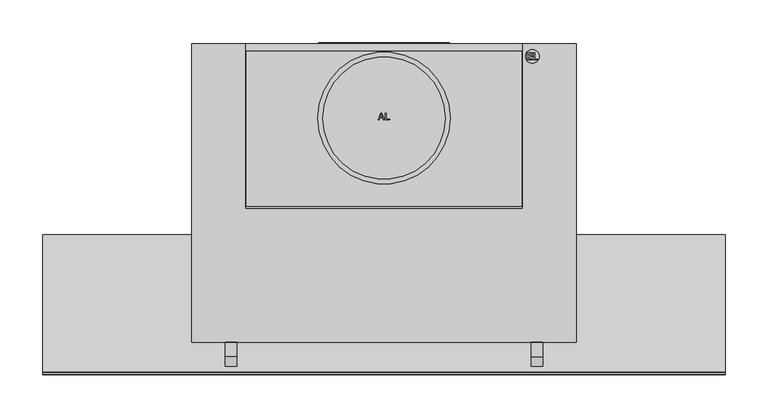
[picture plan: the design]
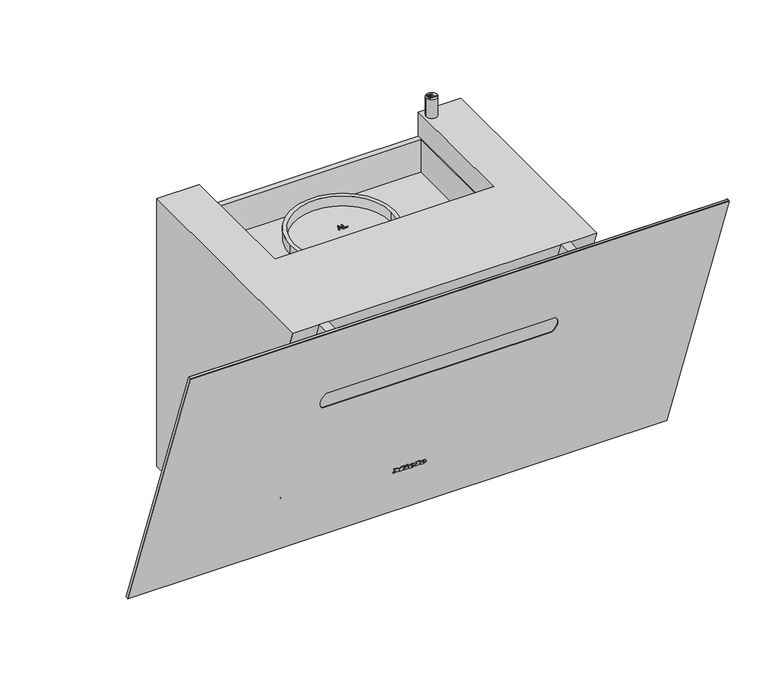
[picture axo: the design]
"""IFC4 building model written with IfcOpenShell, lengths in millimetres: proxy geometry."""

from ifc_helpers import new_model, si_unit, point, frame, frame_2d, origin, origin_with_axes, place, context, project, spatial, polyline, circle_curve, ellipse_curve, trimmed, segment, composite_curve, outline, extrude, faceted_brep, source, transform, mapped, element, save
from ifc_brep_helpers import plane_surface, cylinder_surface, revolved_surface, extruded_surface, advanced_brep


def specialty_equipment_e31fde03(model_context):
    return source(origin(), model_context, "Body", "SolidModel", [
        extrude(outline(polyline([(0.0, 0.0), (0.968, 0.0), (0.968, 5.352), (0.0, 5.352), (0.0, 6.696), (3.52, 6.696), (3.52, 5.352), (2.56, 5.352), (2.56, 1.9488753), (6.136, 6.696), (9.728, 1.8807777), (9.728, 5.352), (8.744, 5.352), (8.744, 6.696), (15.128, 6.696), (15.128, 5.352), (14.112, 5.352), (14.112, 0.0), (15.128, 0.0), (15.128, -1.304), (10.256, -1.304), (7.92, 1.696), (5.576, -1.304), (0.0, -1.304), (0.0, 0.0)])), frame((-24.271984, -261.1380975, 82.2921818), z_axis=(0.0, 0.9396926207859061, 0.34202014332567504), x_axis=(1.0, 0.0, 0.0)), (0.0, 0.0, 1.0), 1.0),
        extrude(outline(polyline([(0.0, 0.0), (0.96, 0.0), (0.96, 5.352), (0.0, 5.352), (0.0, 6.696), (6.488, 6.696), (6.488, 5.352), (5.504, 5.352), (5.504, -1.304), (0.0, -1.304), (0.0, 0.0)])), frame((8.192016, -261.1380975, 82.2921818), z_axis=(0.0, 0.9396926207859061, 0.34202014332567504), x_axis=(1.0, 0.0, 0.0)), (0.0, 0.0, 1.0), 1.0),
        extrude(outline(polyline([(0.0, 0.0), (1.4315306, 0.0), (1.4390414, -2.9920869), (0.0109086, -2.9993294), (0.0, 0.0)])), frame((-6.351984, -261.4226582, 83.074006), z_axis=(0.0, 0.9396926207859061, 0.342020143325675), x_axis=(0.42472021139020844, 0.30963927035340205, -0.8507269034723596)), (0.0, 0.0, 1.0), 1.0),
        extrude(outline(polyline([(0.4933907, 2.4141097), (1.7898156, 3.022309), (2.1941493, 2.1604399), (5.1636141, 3.5535222), (4.7592805, 4.4153913), (5.9760369, 4.9862153), (8.6568708, -0.728194), (7.4401145, -1.299018), (7.0459741, -0.4588767), (2.7800843, -2.4601583), (0.4933907, 2.4141097)])), frame((-6.351984, -261.4226582, 83.074006), z_axis=(0.0, 0.9396926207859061, 0.342020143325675), x_axis=(0.42472021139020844, 0.30963927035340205, -0.8507269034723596)), (0.0, 0.0, 1.0), 1.0),
        advanced_brep(
        [(2.392016, -259.4964008, 77.7816572), (2.392016, -259.7727531, 78.5409288), (7.744016, -259.7727531, 78.5409288), (-1.567984, -259.7727531, 78.5409288), (0.632016, -258.8479306, 76.0), (7.608016, -259.4964008, 77.7816572), (5.192016, -259.4964008, 77.7816572), (3.288016, -259.1899507, 76.9396926), (2.392016, -260.1229817, 79.5031741), (2.392016, -260.4212233, 80.3225861), (3.760016, -260.4212233, 80.3225861), (3.760016, -260.1229817, 79.5031741), (2.392016, -258.5567082, 78.1236774), (3.288016, -258.2502581, 77.2817128), (5.192016, -258.5567082, 78.1236774), (7.608016, -258.5567082, 78.1236774), (0.632016, -257.908238, 76.3420201), (-1.567984, -258.8330604, 78.882949), (7.744016, -258.8330604, 78.882949), (2.392016, -258.8330604, 78.882949), (2.392016, -259.1832891, 79.8451942), (3.760016, -259.1832891, 79.8451942), (3.760016, -259.4815306, 80.6646062), (2.392016, -259.4815306, 80.6646062)],
        [
            (0, 1),
            (1, 2),
            (2, 3, ellipse_curve(frame((3.088016, -259.7727531, 78.5409288), z_axis=(0.0, -0.9396926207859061, -0.34202014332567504), x_axis=(-1.0, 0.0, 0.0)), 4.656, 3.848)),
            (3, 4, circle_curve(frame((1.5280596, -259.8657825, 78.7965252), z_axis=(0.0, -0.9396926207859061, -0.34202014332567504), x_axis=(0.0, 0.34202014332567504, -0.9396926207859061)), 3.1079688)),
            (4, 5, circle_curve(frame((2.9948096, -260.5881291, 80.7811561), z_axis=(0.0, -0.9396926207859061, -0.34202014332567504), x_axis=(0.0, 0.34202014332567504, -0.9396926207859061)), 5.6098607)),
            (5, 6),
            (6, 7, circle_curve(frame((3.6790748, -259.7508638, 78.4807885), z_axis=(0.0, 0.9396926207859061, 0.34202014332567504), x_axis=(0.0, 0.34202014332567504, -0.9396926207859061)), 1.6859795)),
            (7, 0, circle_curve(frame((3.288016, -259.4964008, 77.7816572), z_axis=(0.0, 0.9396926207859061, 0.34202014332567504), x_axis=(0.0, 0.34202014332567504, -0.9396926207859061)), 0.896)),
            (8, 9),
            (9, 10, circle_curve(frame((3.076016, -260.4212233, 80.3225861), z_axis=(0.0, 0.9396926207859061, 0.34202014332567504), x_axis=(0.0, 0.34202014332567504, -0.9396926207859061)), 0.684)),
            (10, 11),
            (11, 8),
            (12, 13, circle_curve(frame((3.288016, -258.5567082, 78.1236774), z_axis=(0.0, -0.9396926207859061, -0.34202014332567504), x_axis=(0.0, 0.34202014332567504, -0.9396926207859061)), 0.896)),
            (13, 14, circle_curve(frame((3.6790748, -258.8111712, 78.8228087), z_axis=(0.0, -0.9396926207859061, -0.34202014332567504), x_axis=(0.0, 0.34202014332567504, -0.9396926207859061)), 1.6859795)),
            (14, 15),
            (15, 16, circle_curve(frame((2.9948096, -259.6484365, 81.1231762), z_axis=(0.0, 0.9396926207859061, 0.34202014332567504), x_axis=(0.0, 0.34202014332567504, -0.9396926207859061)), 5.6098607)),
            (16, 17, circle_curve(frame((1.5280596, -258.9260899, 79.1385454), z_axis=(0.0, 0.9396926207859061, 0.34202014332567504), x_axis=(0.0, 0.34202014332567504, -0.9396926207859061)), 3.1079688)),
            (17, 18, ellipse_curve(frame((3.088016, -258.8330604, 78.882949), z_axis=(0.0, 0.9396926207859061, 0.34202014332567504), x_axis=(-1.0, 0.0, 0.0)), 4.656, 3.848)),
            (18, 19),
            (19, 12),
            (20, 21),
            (21, 22),
            (22, 23, circle_curve(frame((3.076016, -259.4815306, 80.6646062), z_axis=(0.0, -0.9396926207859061, -0.34202014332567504), x_axis=(0.0, 0.34202014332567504, -0.9396926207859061)), 0.684)),
            (23, 20),
            (0, 12),
            (19, 1),
            (18, 2),
            (5, 15),
            (14, 6),
            (17, 3),
            (13, 7),
            (16, 4),
            (8, 20),
            (23, 9),
            (22, 10),
            (21, 11),
        ],
        [
            plane_surface(frame((2.392016, -259.7727531, 78.5409288), z_axis=(0.0, -0.9396926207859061, -0.34202014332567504), x_axis=(0.0, -0.34202014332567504, 0.9396926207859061))),
            plane_surface(frame((2.392016, -258.8330604, 78.882949), z_axis=(0.0, 0.9396926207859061, 0.34202014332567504), x_axis=(0.0, 0.34202014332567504, -0.9396926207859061))),
            plane_surface(frame((2.392016, -259.4964008, 77.7816572), z_axis=(1.0, 0.0, 0.0), x_axis=(0.0, 0.9396926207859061, 0.34202014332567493))),
            plane_surface(frame((2.392016, -259.7727531, 78.5409288), z_axis=(0.0, 0.34202014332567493, -0.9396926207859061), x_axis=(0.0, 0.9396926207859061, 0.34202014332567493))),
            plane_surface(frame((7.608016, -259.4964008, 77.7816572), z_axis=(0.0, -0.34202014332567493, 0.9396926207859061), x_axis=(0.0, 0.9396926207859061, 0.34202014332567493))),
            extruded_surface(trimmed(ellipse_curve(frame((3.088016, -257.8933678, 79.2249691), z_axis=(0.0, -0.9396926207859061, -0.34202014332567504), x_axis=(-1.0, 0.0, 0.0)), 4.656, 3.848), [point((7.744016, -257.8933678, 79.2249691))], [point((-1.567984, -257.8933678, 79.2249691))], True, "CARTESIAN"), (0.0, -0.9396926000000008, -0.34202009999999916), 0.9999999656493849),
            revolved_surface(polyline([(3.6790748, -258.2345321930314, 77.23850622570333), (3.6790748, -259.1742248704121, 76.89648606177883)]), (3.6790748, -258.8111712, 78.8228087), (0.0, 0.9396926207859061, 0.34202014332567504)),
            revolved_surface(polyline([(3.288016, -258.25025810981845, 77.28171282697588), (3.288016, -259.1899507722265, 76.93969266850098)]), (3.288016, -258.5567082, 78.1236774), (0.0, 0.9396926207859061, 0.34202014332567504)),
            cylinder_surface(frame((1.5280596, -258.9260899, 79.1385454), z_axis=(0.0, -0.9396926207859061, -0.34202014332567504), x_axis=(0.0, 0.34202014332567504, -0.9396926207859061)), 3.1079688),
            cylinder_surface(frame((2.9948096, -259.6484365, 81.1231762), z_axis=(0.0, -0.9396926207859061, -0.34202014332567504), x_axis=(0.0, 0.34202014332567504, -0.9396926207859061)), 5.6098607),
            plane_surface(frame((2.392016, -260.1229817, 79.5031741), z_axis=(1.0, 0.0, 0.0), x_axis=(0.0, 0.9396926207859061, 0.34202014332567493))),
            revolved_surface(polyline([(3.076016, -259.2475888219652, 80.02185644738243), (3.076016, -260.1872814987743, 79.67983628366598)]), (3.076016, -259.4815306, 80.6646062), (0.0, 0.9396926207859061, 0.34202014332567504)),
            plane_surface(frame((3.760016, -260.4212233, 80.3225861), z_axis=(-1.0, 0.0, 0.0), x_axis=(0.0, 0.9396926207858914, 0.3420201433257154))),
            plane_surface(frame((3.760016, -260.1229817, 79.5031741), z_axis=(0.0, -0.34202014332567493, 0.9396926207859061), x_axis=(0.0, 0.9396926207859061, 0.34202014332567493))),
        ],
        [
            (0, [[1, 2, 3, 4, 5, 6, 7, 8], [9, 10, 11, 12]]),
            (1, [[13, 14, 15, 16, 17, 18, 19, 20], [21, 22, 23, 24]]),
            (2, [[-1, 25, -20, 26]]),
            (3, [[-2, -26, -19, 27]]),
            (4, [[-6, 28, -15, 29]]),
            (5, [[-3, -27, -18, 30]]),
            (6, [[-7, -29, -14, 31]]),
            (7, [[-8, -31, -13, -25]]),
            (8, [[-4, -30, -17, 32]]),
            (9, [[-5, -32, -16, -28]]),
            (10, [[-9, 33, -24, 34]]),
            (11, [[-10, -34, -23, 35]]),
            (12, [[-11, -35, -22, 36]]),
            (13, [[-12, -36, -21, -33]]),
        ],
    ),
        advanced_brep(
        [(19.088016, -259.4964008, 77.7816572), (19.088016, -259.7727531, 78.5409288), (24.440016, -259.7727531, 78.5409288), (15.128016, -259.7727531, 78.5409288), (17.328016, -258.8479306, 76.0), (24.304016, -259.4964008, 77.7816572), (21.888016, -259.4964008, 77.7816572), (19.984016, -259.1899507, 76.9396926), (19.088016, -260.1229817, 79.5031741), (19.088016, -260.4212233, 80.3225861), (20.456016, -260.4212233, 80.3225861), (20.456016, -260.1229817, 79.5031741), (19.088016, -258.5567082, 78.1236774), (19.984016, -258.2502581, 77.2817128), (21.888016, -258.5567082, 78.1236774), (24.304016, -258.5567082, 78.1236774), (17.328016, -257.908238, 76.3420201), (15.128016, -258.8330604, 78.882949), (24.440016, -258.8330604, 78.882949), (19.088016, -258.8330604, 78.882949), (19.088016, -259.1832891, 79.8451942), (20.456016, -259.1832891, 79.8451942), (20.456016, -259.4815306, 80.6646062), (19.088016, -259.4815306, 80.6646062)],
        [
            (0, 1),
            (1, 2),
            (2, 3, ellipse_curve(frame((19.784016, -259.7727531, 78.5409288), z_axis=(0.0, -0.9396926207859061, -0.34202014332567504), x_axis=(-1.0, 0.0, 0.0)), 4.656, 3.848)),
            (3, 4, circle_curve(frame((18.2240596, -259.8657825, 78.7965252), z_axis=(0.0, -0.9396926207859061, -0.34202014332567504), x_axis=(0.0, 0.34202014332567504, -0.9396926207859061)), 3.1079688)),
            (4, 5, circle_curve(frame((19.6908096, -260.5881291, 80.7811561), z_axis=(0.0, -0.9396926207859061, -0.34202014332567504), x_axis=(0.0, 0.34202014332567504, -0.9396926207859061)), 5.6098607)),
            (5, 6),
            (6, 7, circle_curve(frame((20.3750748, -259.7508638, 78.4807885), z_axis=(0.0, 0.9396926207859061, 0.34202014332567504), x_axis=(0.0, 0.34202014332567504, -0.9396926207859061)), 1.6859795)),
            (7, 0, circle_curve(frame((19.984016, -259.4964008, 77.7816572), z_axis=(0.0, 0.9396926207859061, 0.34202014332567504), x_axis=(0.0, 0.34202014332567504, -0.9396926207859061)), 0.896)),
            (8, 9),
            (9, 10, circle_curve(frame((19.772016, -260.4212233, 80.3225861), z_axis=(0.0, 0.9396926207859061, 0.34202014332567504), x_axis=(0.0, 0.34202014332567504, -0.9396926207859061)), 0.684)),
            (10, 11),
            (11, 8),
            (12, 13, circle_curve(frame((19.984016, -258.5567082, 78.1236774), z_axis=(0.0, -0.9396926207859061, -0.34202014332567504), x_axis=(0.0, 0.34202014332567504, -0.9396926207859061)), 0.896)),
            (13, 14, circle_curve(frame((20.3750748, -258.8111712, 78.8228087), z_axis=(0.0, -0.9396926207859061, -0.34202014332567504), x_axis=(0.0, 0.34202014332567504, -0.9396926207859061)), 1.6859795)),
            (14, 15),
            (15, 16, circle_curve(frame((19.6908096, -259.6484365, 81.1231762), z_axis=(0.0, 0.9396926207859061, 0.34202014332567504), x_axis=(0.0, 0.34202014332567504, -0.9396926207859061)), 5.6098607)),
            (16, 17, circle_curve(frame((18.2240596, -258.9260899, 79.1385454), z_axis=(0.0, 0.9396926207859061, 0.34202014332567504), x_axis=(0.0, 0.34202014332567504, -0.9396926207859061)), 3.1079688)),
            (17, 18, ellipse_curve(frame((19.784016, -258.8330604, 78.882949), z_axis=(0.0, 0.9396926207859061, 0.34202014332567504), x_axis=(-1.0, 0.0, 0.0)), 4.656, 3.848)),
            (18, 19),
            (19, 12),
            (20, 21),
            (21, 22),
            (22, 23, circle_curve(frame((19.772016, -259.4815306, 80.6646062), z_axis=(0.0, -0.9396926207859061, -0.34202014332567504), x_axis=(0.0, 0.34202014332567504, -0.9396926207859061)), 0.684)),
            (23, 20),
            (0, 12),
            (19, 1),
            (18, 2),
            (5, 15),
            (14, 6),
            (17, 3),
            (13, 7),
            (16, 4),
            (8, 20),
            (23, 9),
            (22, 10),
            (21, 11),
        ],
        [
            plane_surface(frame((19.088016, -259.7727531, 78.5409288), z_axis=(0.0, -0.9396926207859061, -0.34202014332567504), x_axis=(0.0, -0.34202014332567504, 0.9396926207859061))),
            plane_surface(frame((19.088016, -258.8330604, 78.882949), z_axis=(0.0, 0.9396926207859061, 0.34202014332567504), x_axis=(0.0, 0.34202014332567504, -0.9396926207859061))),
            plane_surface(frame((19.088016, -259.4964008, 77.7816572), z_axis=(1.0, 0.0, 0.0), x_axis=(0.0, 0.9396926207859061, 0.34202014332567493))),
            plane_surface(frame((19.088016, -259.7727531, 78.5409288), z_axis=(0.0, 0.34202014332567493, -0.9396926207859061), x_axis=(0.0, 0.9396926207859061, 0.34202014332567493))),
            plane_surface(frame((24.304016, -259.4964008, 77.7816572), z_axis=(0.0, -0.34202014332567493, 0.9396926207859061), x_axis=(0.0, 0.9396926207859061, 0.34202014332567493))),
            extruded_surface(trimmed(ellipse_curve(frame((19.784016, -257.8933678, 79.2249691), z_axis=(0.0, -0.9396926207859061, -0.34202014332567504), x_axis=(-1.0, 0.0, 0.0)), 4.656, 3.848), [point((24.440016, -257.8933678, 79.2249691))], [point((15.128016, -257.8933678, 79.2249691))], True, "CARTESIAN"), (0.0, -0.9396926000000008, -0.34202009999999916), 0.9999999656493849),
            revolved_surface(polyline([(20.3750748, -258.2345321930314, 77.23850622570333), (20.3750748, -259.1742248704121, 76.89648606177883)]), (20.3750748, -258.8111712, 78.8228087), (0.0, 0.9396926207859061, 0.34202014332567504)),
            revolved_surface(polyline([(19.984016, -258.25025810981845, 77.28171282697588), (19.984016, -259.1899507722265, 76.93969266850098)]), (19.984016, -258.5567082, 78.1236774), (0.0, 0.9396926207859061, 0.34202014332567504)),
            cylinder_surface(frame((18.2240596, -258.9260899, 79.1385454), z_axis=(0.0, -0.9396926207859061, -0.34202014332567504), x_axis=(0.0, 0.34202014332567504, -0.9396926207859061)), 3.1079688),
            cylinder_surface(frame((19.6908096, -259.6484365, 81.1231762), z_axis=(0.0, -0.9396926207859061, -0.34202014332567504), x_axis=(0.0, 0.34202014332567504, -0.9396926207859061)), 5.6098607),
            plane_surface(frame((19.088016, -260.1229817, 79.5031741), z_axis=(1.0, 0.0, 0.0), x_axis=(0.0, 0.9396926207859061, 0.34202014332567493))),
            revolved_surface(polyline([(19.772016, -259.2475888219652, 80.02185644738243), (19.772016, -260.1872814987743, 79.67983628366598)]), (19.772016, -259.4815306, 80.6646062), (0.0, 0.9396926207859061, 0.34202014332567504)),
            plane_surface(frame((20.456016, -260.4212233, 80.3225861), z_axis=(-1.0, 0.0, 0.0), x_axis=(0.0, 0.9396926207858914, 0.3420201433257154))),
            plane_surface(frame((20.456016, -260.1229817, 79.5031741), z_axis=(0.0, -0.34202014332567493, 0.9396926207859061), x_axis=(0.0, 0.9396926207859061, 0.34202014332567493))),
        ],
        [
            (0, [[1, 2, 3, 4, 5, 6, 7, 8], [9, 10, 11, 12]]),
            (1, [[13, 14, 15, 16, 17, 18, 19, 20], [21, 22, 23, 24]]),
            (2, [[-1, 25, -20, 26]]),
            (3, [[-2, -26, -19, 27]]),
            (4, [[-6, 28, -15, 29]]),
            (5, [[-3, -27, -18, 30]]),
            (6, [[-7, -29, -14, 31]]),
            (7, [[-8, -31, -13, -25]]),
            (8, [[-4, -30, -17, 32]]),
            (9, [[-5, -32, -16, -28]]),
            (10, [[-9, 33, -24, 34]]),
            (11, [[-10, -34, -23, 35]]),
            (12, [[-11, -35, -22, 36]]),
            (13, [[-12, -36, -21, -33]]),
        ],
    ),
        advanced_brep(
        [(-198.5, -231.2422284, 80.5173231), (-198.5, -240.9843308, 107.2835295), (-198.5, -235.8312261, 109.4708926), (-198.5, -225.8887113, 82.1540576), (-198.5, -250.514978, 76.8365225), (-198.5, -258.1140866, 97.7149017), (-198.5, -258.4754112, 96.7430581), (-198.5, -251.4164577, 77.3487429), (-198.5, -254.9459345, 87.0459005), (-198.5, -230.9198317, 95.7906867)],
        [
            (0, 1, circle_curve(frame((-198.5, -236.1132796, 93.9004263), z_axis=(0.0, 0.9396926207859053, 0.3420201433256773), x_axis=(0.0, -0.3420201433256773, 0.9396926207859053)), 14.2420009)),
            (1, 2),
            (2, 3, circle_curve(frame((-198.5, -230.8599687, 95.8124751), z_axis=(0.0, -0.9396926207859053, -0.3420201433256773), x_axis=(0.0, -0.3420201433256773, 0.9396926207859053)), 14.5349844)),
            (3, 0),
            (4, 5, circle_curve(frame((-198.5, -254.3145323, 87.2757121), z_axis=(0.0, 0.9396926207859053, 0.3420201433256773), x_axis=(0.0, -0.3420201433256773, 0.9396926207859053)), 11.1091535)),
            (5, 1),
            (0, 4),
            (6, 7, circle_curve(frame((-198.5, -254.9459345, 87.0459005), z_axis=(0.0, 0.9396926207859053, 0.3420201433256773), x_axis=(0.0, -0.3420201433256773, 0.9396926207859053)), 10.3194996)),
            (7, 4),
            (4, 5, circle_curve(frame((-198.5, -254.3145323, 87.2757121), z_axis=(0.0, -0.9396926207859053, -0.3420201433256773), x_axis=(0.0, -0.3420201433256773, 0.9396926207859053)), 11.1091535)),
            (5, 6),
            (8, 7),
            (6, 8),
            (2, 9),
            (9, 3),
            (2, 3, circle_curve(frame((-198.5, -230.9198317, 95.7906867), z_axis=(0.0, 0.9396926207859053, 0.3420201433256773), x_axis=(0.0, -0.3420201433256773, 0.9396926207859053)), 14.535124)),
            (1, 0, circle_curve(frame((-198.5, -236.1132796, 93.9004263), z_axis=(0.0, 0.9396926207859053, 0.3420201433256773), x_axis=(0.0, -0.3420201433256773, 0.9396926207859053)), 14.2420009)),
            (7, 6, circle_curve(frame((-198.5, -254.9459345, 87.0459005), z_axis=(0.0, 0.9396926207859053, 0.3420201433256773), x_axis=(0.0, -0.3420201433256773, 0.9396926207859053)), 10.3194996)),
        ],
        [
            revolved_surface(polyline([(-198.5, -235.8312261, 109.4708926), (-198.5, -240.9843308, 107.2835295)]), (-198.5, -255.2773841, 86.9252627), (0.0, -0.9396926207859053, -0.3420201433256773)),
            revolved_surface(polyline([(-198.5, -240.9843308, 107.2835295), (-198.5, -258.1140866, 97.7149017)]), (-198.5, -255.2773841, 86.9252627), (0.0, -0.9396926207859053, -0.3420201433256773)),
            revolved_surface(polyline([(-198.5, -258.1140866, 97.7149017), (-198.5, -258.4754112, 96.7430581)]), (-198.5, -255.2773841, 86.9252627), (0.0, -0.9396926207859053, -0.3420201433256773)),
            plane_surface(frame((-198.5, -254.9459345, 87.0459005), z_axis=(0.0, -0.9396926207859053, -0.3420201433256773), x_axis=(0.0, -0.3420201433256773, 0.9396926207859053))),
            plane_surface(frame((-198.5, -230.9198317, 95.7906867), z_axis=(0.0, 0.9396926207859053, 0.3420201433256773), x_axis=(0.0, -0.3420201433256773, 0.9396926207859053))),
        ],
        [
            (0, [[1, 2, 3, 4]]),
            (1, [[5, 6, -1, 7]]),
            (2, [[8, 9, 10, 11]]),
            (3, [[12, -8, 13]]),
            (4, [[-3, 14, 15]]),
            (4, [[16, -15, -14]]),
            (0, [[17, -4, -16, -2]]),
            (1, [[-10, -7, -17, -6]]),
            (2, [[18, -11, -5, -9]]),
            (3, [[-13, -18, -12]]),
        ],
    ),
        advanced_brep(
        [(-198.5, -262.8067778, 105.2732379), (-198.5, -249.4001153, 68.4387353), (-198.5, -252.3199878, 80.8696014), (-198.5, -257.0531232, 93.8737841), (-198.5, -250.699917, 68.232867), (-198.5, -263.9348133, 104.5954458), (-198.5, -257.3173652, 86.4141564), (-198.5, -254.6865555, 87.3716928)],
        [
            (0, 1, circle_curve(frame((-198.5, -256.1034466, 86.8559866), z_axis=(0.0, 0.9396926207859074, 0.34202014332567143), x_axis=(0.0, -0.34202014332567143, 0.9396926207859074)), 19.5992294)),
            (1, 2),
            (2, 3, circle_curve(frame((-198.5, -254.6865555, 87.3716928), z_axis=(0.0, -0.9396926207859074, -0.34202014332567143), x_axis=(0.0, -0.34202014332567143, 0.9396926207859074)), 6.9193811)),
            (3, 0),
            (1, 0, circle_curve(frame((-198.5, -256.1034466, 86.8559866), z_axis=(0.0, 0.9396926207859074, 0.34202014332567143), x_axis=(0.0, -0.34202014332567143, 0.9396926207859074)), 19.5992294)),
            (3, 2, circle_curve(frame((-198.5, -254.6865555, 87.3716928), z_axis=(0.0, -0.9396926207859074, -0.34202014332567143), x_axis=(0.0, -0.34202014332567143, 0.9396926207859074)), 6.9193811)),
            (4, 5, circle_curve(frame((-198.5, -257.3173652, 86.4141564), z_axis=(0.0, 0.9396926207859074, 0.34202014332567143), x_axis=(0.0, -0.34202014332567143, 0.9396926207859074)), 19.3481241)),
            (5, 0),
            (1, 4),
            (5, 4, circle_curve(frame((-198.5, -257.3173652, 86.4141564), z_axis=(0.0, 0.9396926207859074, 0.34202014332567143), x_axis=(0.0, -0.34202014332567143, 0.9396926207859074)), 19.3481241)),
            (6, 5),
            (4, 6),
            (3, 7),
            (7, 2),
        ],
        [
            revolved_surface(polyline([(-198.5, -257.0531232, 93.8737841), (-198.5, -262.8067778, 105.2732379)]), (-198.5, -254.6865555, 87.3716928), (0.0, -0.9396926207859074, -0.34202014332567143)),
            revolved_surface(polyline([(-198.5, -262.8067778, 105.2732379), (-198.5, -263.9348133, 104.5954458)]), (-198.5, -254.6865555, 87.3716928), (0.0, -0.9396926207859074, -0.34202014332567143)),
            plane_surface(frame((-198.5, -257.3173652, 86.4141564), z_axis=(0.0, -0.9396926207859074, -0.34202014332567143), x_axis=(0.0, -0.34202014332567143, 0.9396926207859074))),
            plane_surface(frame((-198.5, -254.6865555, 87.3716928), z_axis=(0.0, 0.9396926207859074, 0.34202014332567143), x_axis=(0.0, -0.34202014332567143, 0.9396926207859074))),
        ],
        [
            (0, [[1, 2, 3, 4]]),
            (0, [[5, -4, 6, -2]]),
            (1, [[7, 8, -5, 9]]),
            (1, [[10, -9, -1, -8]]),
            (2, [[11, -7, 12]]),
            (2, [[-12, -10, -11]]),
            (3, [[-6, 13, 14]]),
            (3, [[-3, -14, -13]]),
        ],
    ),
        advanced_brep(
        [(198.5, -225.9091808, 82.1477994), (198.5, -235.8509293, 109.4625291), (198.5, -240.9843308, 107.2835295), (198.5, -231.2422284, 80.5173231), (198.5, -258.1140866, 97.7149017), (198.5, -250.514978, 76.8365225), (198.5, -230.9018417, 95.8650227), (198.5, -258.4754112, 96.7430581), (198.5, -251.4164577, 77.3487429), (198.5, -254.9459345, 87.0459005)],
        [
            (0, 1, circle_curve(frame((198.5, -230.8800551, 95.8051643), z_axis=(0.0, -0.9396926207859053, -0.3420201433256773), x_axis=(0.0, -0.3420201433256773, 0.9396926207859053)), 14.5338641)),
            (1, 2),
            (2, 3, circle_curve(frame((198.5, -236.1132796, 93.9004263), z_axis=(0.0, 0.9396926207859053, 0.3420201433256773), x_axis=(0.0, -0.3420201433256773, 0.9396926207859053)), 14.2420009)),
            (3, 0),
            (2, 4),
            (4, 5, circle_curve(frame((198.5, -254.3145323, 87.2757121), z_axis=(0.0, 0.9396926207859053, 0.3420201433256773), x_axis=(0.0, -0.3420201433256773, 0.9396926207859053)), 11.1091535)),
            (5, 3),
            (6, 1),
            (0, 6),
            (0, 1, circle_curve(frame((198.5, -230.8800551, 95.8051643), z_axis=(0.0, 0.9396926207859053, 0.3420201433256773), x_axis=(0.0, -0.3420201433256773, 0.9396926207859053)), 14.5338641)),
            (3, 2, circle_curve(frame((198.5, -236.1132796, 93.9004263), z_axis=(0.0, 0.9396926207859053, 0.3420201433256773), x_axis=(0.0, -0.3420201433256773, 0.9396926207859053)), 14.2420009)),
            (5, 4, circle_curve(frame((198.5, -254.3145323, 87.2757121), z_axis=(0.0, 0.9396926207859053, 0.3420201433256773), x_axis=(0.0, -0.3420201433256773, 0.9396926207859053)), 11.1091535)),
            (4, 7),
            (7, 8, circle_curve(frame((198.5, -254.9459345, 87.0459005), z_axis=(0.0, 0.9396926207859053, 0.3420201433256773), x_axis=(0.0, -0.3420201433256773, 0.9396926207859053)), 10.3194996)),
            (8, 5),
            (8, 7, circle_curve(frame((198.5, -254.9459345, 87.0459005), z_axis=(0.0, 0.9396926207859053, 0.3420201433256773), x_axis=(0.0, -0.3420201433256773, 0.9396926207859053)), 10.3194996)),
            (7, 9),
            (9, 8),
        ],
        [
            revolved_surface(polyline([(198.5, -240.9843308, 107.2835295), (198.5, -235.8509293, 109.4625291)]), (198.5, -255.2773841, 86.9252627), (0.0, 0.9396926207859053, 0.3420201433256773)),
            revolved_surface(polyline([(198.5, -258.1140866, 97.7149017), (198.5, -240.9843308, 107.2835295)]), (198.5, -255.2773841, 86.9252627), (0.0, 0.9396926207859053, 0.3420201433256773)),
            plane_surface(frame((198.5, -230.8800551, 95.8051643), z_axis=(0.0, 0.9396926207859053, 0.3420201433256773), x_axis=(0.0, -0.3420201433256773, 0.9396926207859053))),
            revolved_surface(polyline([(198.5, -258.4754112, 96.7430581), (198.5, -258.1140866, 97.7149017)]), (198.5, -255.2773841, 86.9252627), (0.0, 0.9396926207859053, 0.3420201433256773)),
            plane_surface(frame((198.5, -254.9459345, 87.0459005), z_axis=(0.0, -0.9396926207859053, -0.3420201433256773), x_axis=(0.0, -0.3420201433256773, 0.9396926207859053))),
        ],
        [
            (0, [[1, 2, 3, 4]]),
            (1, [[-3, 5, 6, 7]]),
            (2, [[8, -1, 9]]),
            (2, [[-9, 10, -8]]),
            (0, [[-10, -4, 11, -2]]),
            (1, [[-11, -7, 12, -5]]),
            (3, [[-6, 13, 14, 15]]),
            (3, [[-12, -15, 16, -13]]),
            (4, [[-14, 17, 18]]),
            (4, [[-16, -18, -17]]),
        ],
    ),
        advanced_brep(
        [(198.5, -252.3199878, 80.8696014), (198.5, -257.0531232, 93.8737841), (198.5, -262.8067778, 105.2732379), (198.5, -249.4001153, 68.4387353), (198.5, -263.9348133, 104.5954458), (198.5, -250.699917, 68.232867), (198.5, -257.3173652, 86.4141564), (198.5, -254.6865555, 87.3716928)],
        [
            (0, 1, circle_curve(frame((198.5, -254.6865555, 87.3716928), z_axis=(0.0, -0.9396926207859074, -0.34202014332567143), x_axis=(0.0, -0.34202014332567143, 0.9396926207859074)), 6.9193811)),
            (1, 2),
            (2, 3, circle_curve(frame((198.5, -256.1034466, 86.8559866), z_axis=(0.0, 0.9396926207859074, 0.34202014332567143), x_axis=(0.0, -0.34202014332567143, 0.9396926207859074)), 19.5992294)),
            (3, 0),
            (1, 0, circle_curve(frame((198.5, -254.6865555, 87.3716928), z_axis=(0.0, -0.9396926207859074, -0.34202014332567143), x_axis=(0.0, -0.34202014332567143, 0.9396926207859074)), 6.9193811)),
            (3, 2, circle_curve(frame((198.5, -256.1034466, 86.8559866), z_axis=(0.0, 0.9396926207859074, 0.34202014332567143), x_axis=(0.0, -0.34202014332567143, 0.9396926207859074)), 19.5992294)),
            (2, 4),
            (4, 5, circle_curve(frame((198.5, -257.3173652, 86.4141564), z_axis=(0.0, 0.9396926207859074, 0.34202014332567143), x_axis=(0.0, -0.34202014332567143, 0.9396926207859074)), 19.3481241)),
            (5, 3),
            (5, 4, circle_curve(frame((198.5, -257.3173652, 86.4141564), z_axis=(0.0, 0.9396926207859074, 0.34202014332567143), x_axis=(0.0, -0.34202014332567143, 0.9396926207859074)), 19.3481241)),
            (4, 6),
            (6, 5),
            (7, 1),
            (0, 7),
        ],
        [
            revolved_surface(polyline([(198.5, -262.8067778, 105.2732379), (198.5, -257.0531232, 93.8737841)]), (198.5, -254.6865555, 87.3716928), (0.0, 0.9396926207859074, 0.34202014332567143)),
            revolved_surface(polyline([(198.5, -263.9348133, 104.5954458), (198.5, -262.8067778, 105.2732379)]), (198.5, -254.6865555, 87.3716928), (0.0, 0.9396926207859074, 0.34202014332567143)),
            plane_surface(frame((198.5, -257.3173652, 86.4141564), z_axis=(0.0, -0.9396926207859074, -0.34202014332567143), x_axis=(0.0, -0.34202014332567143, 0.9396926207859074))),
            plane_surface(frame((198.5, -254.6865555, 87.3716928), z_axis=(0.0, 0.9396926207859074, 0.34202014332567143), x_axis=(0.0, -0.34202014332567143, 0.9396926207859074))),
        ],
        [
            (0, [[1, 2, 3, 4]]),
            (0, [[5, -4, 6, -2]]),
            (1, [[-3, 7, 8, 9]]),
            (1, [[-6, -9, 10, -7]]),
            (2, [[-8, 11, 12]]),
            (2, [[-10, -12, -11]]),
            (3, [[13, -1, 14]]),
            (3, [[-14, -5, -13]]),
        ],
    ),
        extrude(outline(polyline([(-377.2541471, 415.9959153), (-366.2530147, 420.0), (-348.8949883, 420.0), (-315.0686278, 327.0628384), (-321.2276447, 324.8211395), (-334.9582954, 325.4920509), (-347.6637142, 334.6968691), (-377.2541471, 415.9959153)])), frame((-185.7167767, 0.0, 0.0), z_axis=(1.0, 0.0, 0.0), x_axis=(0.0, 1.0, 0.0)), (0.0, 0.0, 1.0), 13.4088513),
        extrude(outline(polyline([(-377.2541471, 415.9959153), (-366.2530147, 420.0), (-348.8949883, 420.0), (-315.0686278, 327.0628384), (-321.2276447, 324.8211395), (-334.9582954, 325.4920509), (-347.6637142, 334.6968691), (-377.2541471, 415.9959153)])), frame((172.3079253, 0.0, 0.0), z_axis=(1.0, 0.0, 0.0), x_axis=(0.0, 1.0, 0.0)), (0.0, 0.0, 1.0), 13.4088513),
        advanced_brep(
        [(399.0, -387.3899893, 432.0882368), (399.0, -387.1323401, 432.8365045), (-399.0, -387.1323401, 432.8365045), (-399.0, -387.3899893, 432.0882368), (399.0, -227.0596169, -8.4158411), (399.0, -226.3696341, -8.8142029), (399.0, -223.5613092, -7.7920563), (399.0, -223.2772642, -7.0520936), (399.0, -383.5944926, 433.4158714), (399.0, -384.310791, 433.8634644), (-399.0, -384.310791, 433.8634644), (-399.0, -383.5944926, 433.4158714), (-399.0, -223.2772642, -7.0520936), (-399.0, -223.5613092, -7.7920563), (-399.0, -226.3696341, -8.8142029), (-399.0, -227.0596169, -8.4158411), (-170.0000153, -329.0580322, 271.8225017), (-170.0000153, -339.664028, 300.9622357), (169.9999847, -339.664028, 300.9622357), (169.9999847, -329.0580322, 271.8225017), (-170.0000153, -338.7237973, 301.3044517), (-170.0000153, -328.1178015, 272.1647177), (169.9999847, -328.1178015, 272.1647177), (169.9999847, -338.7237973, 301.3044517)],
        [
            (0, 1),
            (1, 2),
            (2, 3),
            (3, 0),
            (0, 4),
            (4, 5),
            (5, 6),
            (6, 7),
            (7, 8),
            (8, 9),
            (9, 1),
            (2, 10),
            (10, 11),
            (11, 12),
            (12, 13),
            (13, 14),
            (14, 15),
            (15, 3),
            (15, 4),
            (16, 17, circle_curve(frame((-150.89824, -334.3610301, 286.3923687), z_axis=(0.0, 0.9396926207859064, 0.3420201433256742), x_axis=(1.0, 0.0, 0.0)), 24.6024517)),
            (17, 18),
            (18, 19, circle_curve(frame((150.8956421, -334.3610301, 286.3923687), z_axis=(0.0, 0.9396926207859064, 0.3420201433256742), x_axis=(1.0, 0.0, 0.0)), 24.6044451)),
            (19, 16),
            (14, 5),
            (13, 6),
            (12, 7),
            (11, 8),
            (10, 9),
            (20, 21, circle_curve(frame((-150.89824, -333.4207994, 286.7345847), z_axis=(0.0, -0.9396926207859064, -0.3420201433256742), x_axis=(1.0, 0.0, 0.0)), 24.6024517)),
            (21, 22),
            (22, 23, circle_curve(frame((150.8956421, -333.4207994, 286.7345847), z_axis=(0.0, -0.9396926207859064, -0.3420201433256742), x_axis=(1.0, 0.0, 0.0)), 24.6044451)),
            (23, 20),
            (20, 17),
            (16, 21),
            (19, 22),
            (18, 23),
        ],
        [
            plane_surface(frame((399.0, -387.1323401, 432.8365045), z_axis=(0.0, -0.9455185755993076, 0.32556815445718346), x_axis=(-1.0, 0.0, 0.0))),
            plane_surface(frame((399.0, -387.1323401, 432.8365045), z_axis=(1.0, 0.0, 0.0), x_axis=(0.0, -0.32556815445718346, -0.9455185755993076))),
            plane_surface(frame((-399.0, -387.1323401, 432.8365045), z_axis=(-1.0, 0.0, 0.0), x_axis=(0.0, 0.32556815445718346, 0.9455185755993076))),
            plane_surface(frame((399.0, -387.3899893, 432.0882368), z_axis=(0.0, -0.939692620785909, -0.34202014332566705), x_axis=(-1.0, 0.0, 0.0))),
            plane_surface(frame((399.0, -227.0596169, -8.4158411), z_axis=(0.0, -0.49999999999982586, -0.8660254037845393), x_axis=(-1.0, 0.0, 0.0))),
            plane_surface(frame((399.0, -226.3696341, -8.8142029), z_axis=(0.0, 0.34202014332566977, -0.939692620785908), x_axis=(-1.0, 0.0, 0.0))),
            plane_surface(frame((399.0, -223.5613092, -7.7920563), z_axis=(0.0, 0.9335804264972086, -0.35836794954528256), x_axis=(-1.0, 0.0, 0.0))),
            plane_surface(frame((399.0, -223.2772642, -7.0520936), z_axis=(0.0, 0.9396926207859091, 0.3420201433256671), x_axis=(-1.0, 0.0, 0.0))),
            plane_surface(frame((399.0, -383.5944926, 433.4158714), z_axis=(0.0, 0.5299192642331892, 0.8480480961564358), x_axis=(-1.0, 0.0, 0.0))),
            plane_surface(frame((399.0, -384.310791, 433.8634644), z_axis=(0.0, -0.3420201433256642, 0.9396926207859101), x_axis=(-1.0, 0.0, 0.0))),
            plane_surface(frame((-126.2957883, -333.4207994, 286.7345847), z_axis=(0.0, -0.9396926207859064, -0.3420201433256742), x_axis=(0.0, 0.3420201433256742, -0.9396926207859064))),
            revolved_surface(polyline([(-126.29578829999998, -334.3610301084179, 286.3923687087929), (-126.29578829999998, -333.4207993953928, 286.7345847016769)]), (-150.89824, -333.4207994, 286.7345847), (0.0, -0.9396926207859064, -0.3420201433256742)),
            plane_surface(frame((-170.0000153, -333.9337198, 270.0478966), z_axis=(0.0, -0.3420201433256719, 0.9396926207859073), x_axis=(0.0, 0.9396926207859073, 0.3420201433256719))),
            revolved_surface(polyline([(175.5000872, -334.3610301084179, 286.3923687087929), (175.5000872, -333.4207993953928, 286.7345847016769)]), (150.8956421, -333.4207994, 286.7345847), (0.0, -0.9396926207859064, -0.3420201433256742)),
            plane_surface(frame((169.9999847, -344.5397156, 299.1876306), z_axis=(0.0, 0.3420201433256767, -0.9396926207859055), x_axis=(0.0, 0.9396926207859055, 0.3420201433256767))),
        ],
        [
            (0, [[1, 2, 3, 4]]),
            (1, [[-1, 5, 6, 7, 8, 9, 10, 11]]),
            (2, [[12, 13, 14, 15, 16, 17, 18, -3]]),
            (3, [[-5, -4, -18, 19], [20, 21, 22, 23]]),
            (4, [[-6, -19, -17, 24]]),
            (5, [[-7, -24, -16, 25]]),
            (6, [[-8, -25, -15, 26]]),
            (7, [[-9, -26, -14, 27]]),
            (8, [[-10, -27, -13, 28]]),
            (9, [[-11, -28, -12, -2]]),
            (10, [[29, 30, 31, 32]]),
            (11, [[-29, 33, -20, 34]]),
            (12, [[-30, -34, -23, 35]]),
            (13, [[-31, -35, -22, 36]]),
            (14, [[-32, -36, -21, -33]]),
        ],
    ),
        faceted_brep([(225.0000193, -349.0, 420.0), (225.0000193, -196.2332597, 0.0), (225.0000193, 0.0, 0.0), (225.0000193, 0.0, 420.0), (-225.0000193, -349.0, 420.0), (-225.0000193, 0.0, 420.0), (-225.0000193, 0.0, 0.0), (-225.0000193, -196.2332597, 0.0), (176.5, -48.0, 0.0), (-176.5, -48.0, 0.0), (-176.5, -181.0, 0.0), (176.5, -181.0, 0.0), (125.0, -12.0, 0.0), (-125.0, -12.0, 0.0), (-125.0, -38.0, 0.0), (125.0, -38.0, 0.0), (-162.2229137, 0.0, 420.0), (-162.2229137, 0.0, 382.5), (162.2229137, 0.0, 382.5), (162.2229137, 0.0, 420.0), (-160.9556997, -9.0, 332.0), (160.9556997, -9.0, 332.0), (160.9556997, -9.0, 382.5), (-160.9556997, -9.0, 382.5), (-160.9556997, -190.0399284, 332.0), (-160.9556997, -190.0399284, 382.5), (160.9556997, -190.0399284, 332.0), (160.9556997, -190.0399284, 382.5), (176.5, -48.0, 11.0), (-176.5, -48.0, 11.0), (125.0, -12.0, 11.0), (-125.0, -12.0, 11.0), (162.2229137, -193.2332597, 420.0), (-162.2229137, -193.2332597, 420.0), (176.5, -181.0, 11.0), (-176.5, -181.0, 11.0), (125.0, -38.0, 11.0), (-125.0, -38.0, 11.0), (162.2229137, -193.2332597, 382.5), (-162.2229137, -193.2332597, 382.5)], [[[0, 1, 2, 3]], [[4, 5, 6, 7]], [[1, 0, 4, 7]], [[2, 1, 7, 6], [8, 9, 10, 11], [12, 13, 14, 15]], [[3, 2, 6, 5, 16, 17, 18, 19]], [[20, 21, 22, 23]], [[24, 20, 23, 25]], [[21, 26, 27, 22]], [[28, 29, 9, 8]], [[30, 31, 13, 12]], [[0, 3, 19, 32, 33, 16, 5, 4]], [[21, 20, 24, 26]], [[26, 24, 25, 27]], [[28, 34, 35, 29]], [[29, 35, 10, 9]], [[35, 34, 11, 10]], [[34, 28, 8, 11]], [[30, 36, 37, 31]], [[31, 37, 14, 13]], [[37, 36, 15, 14]], [[36, 30, 12, 15]], [[32, 38, 39, 33]], [[39, 38, 18, 17], [23, 22, 27, 25]], [[38, 32, 19, 18]], [[33, 39, 17, 16]]]),
        extrude(outline(polyline([(125.0, -12.0), (125.0, -38.0), (-125.0, -38.0), (-125.0, -12.0), (125.0, -12.0)]), holes=[polyline([(-119.0, -31.2), (119.0, -31.2), (119.0, -18.8), (-119.0, -18.8), (-119.0, -31.2)])]), origin_with_axes(), (0.0, 0.0, 1.0), 11.0),
        extrude(outline(polyline([(119.0, -18.8), (119.0, -31.2), (-119.0, -31.2), (-119.0, -18.8), (119.0, -18.8)])), origin_with_axes(), (0.0, 0.0, 1.0), 11.0),
        extrude(outline(polyline([(176.5, -48.0), (176.5, -181.0), (-176.5, -181.0), (-176.5, -48.0), (176.5, -48.0)]), holes=[polyline([(167.5, -57.0), (-167.5, -57.0), (-167.5, -172.0), (167.5, -172.0), (167.5, -57.0)])]), origin_with_axes(), (0.0, 0.0, 1.0), 11.0),
        extrude(outline(polyline([(167.5, -57.0), (167.5, -172.0), (-167.5, -172.0), (-167.5, -57.0), (167.5, -57.0)])), frame((0.0, 0.0, 1.0), z_axis=(0.0, 0.0, 1.0), x_axis=(1.0, 0.0, 0.0)), (0.0, 0.0, 1.0), 10.0),
        extrude(outline(polyline([(-167.5, -98.0), (-124.5000193, -98.0), (-124.5000193, -131.0), (-167.5, -131.0), (-167.5, -98.0)]), holes=[polyline([(-131.0000193, -104.5), (-160.0000193, -104.5), (-160.0000193, -124.5), (-131.0000193, -124.5), (-131.0000193, -104.5)])]), origin_with_axes(), (0.0, 0.0, 1.0), 1.0),
        extrude(outline(polyline([(-131.0000193, -104.5), (-131.0000193, -124.5), (-140.0000193, -124.5), (-140.0000193, -104.5), (-131.0000193, -104.5)])), origin_with_axes(), (0.0, 0.0, 1.0), 1.0),
        extrude(outline(composite_curve([segment(trimmed(circle_curve(frame_2d((0.0, -86.9971466)), 77.2963157), [point((-77.2963157, -86.9971466))], [point((77.2963157, -86.9971466))], False, "CARTESIAN"), True, "CONTINUOUS"), segment(trimmed(circle_curve(frame_2d((0.0, -86.9971466)), 77.2963157), [point((77.2963157, -86.9971466))], [point((-77.2963157, -86.9971466))], False, "CARTESIAN"), True, "CONTINUOUS")], self_intersect=False), holes=[composite_curve([segment(trimmed(circle_curve(frame_2d((0.0, -86.9971466)), 71.617422), [point((-71.617422, -86.9971466))], [point((71.617422, -86.9971466))], True, "CARTESIAN"), True, "CONTINUOUS"), segment(trimmed(circle_curve(frame_2d((0.0, -86.9971466)), 71.617422), [point((71.617422, -86.9971466))], [point((-71.617422, -86.9971466))], True, "CARTESIAN"), True, "CONTINUOUS")], self_intersect=False)]), frame((0.0, 0.0, 332.0), z_axis=(0.0, 0.0, 1.0), x_axis=(1.0, 0.0, 0.0)), (0.0, 0.0, 1.0), 15.9326282),
        extrude(outline(polyline([(-6.835738, -89.2416424), (-3.627807, -81.2051375), (-2.7723587, -81.2051375), (0.4336102, -89.2416424), (-0.6278519, -89.2416424), (-1.5460854, -86.7302346), (-4.8580044, -86.7302346), (-5.7762378, -89.2416424), (-6.835738, -89.2416424)]), holes=[polyline([(-4.4891414, -85.7256715), (-1.9129864, -85.7256715), (-2.6389402, -83.7498999), (-3.2020449, -82.2097006), (-3.7023644, -83.5772407), (-4.4891414, -85.7256715)])]), frame((0.0, 0.0, 347.9326282), z_axis=(0.0, 0.0, 1.0), x_axis=(1.0, 0.0, 0.0)), (0.0, 0.0, 1.0), 1.0),
        extrude(outline(polyline([(1.5068447, -89.2416424), (1.5068447, -81.2051375), (2.5114078, -81.2051375), (2.5114078, -88.2370793), (6.5296602, -88.2370793), (6.5296602, -89.2416424), (1.5068447, -89.2416424)])), frame((0.0, 0.0, 347.9326282), z_axis=(0.0, 0.0, 1.0), x_axis=(1.0, 0.0, 0.0)), (0.0, 0.0, 1.0), 1.0),
        extrude(outline(composite_curve([segment(trimmed(circle_curve(frame_2d((192.5519409, 0.0)), 76.1990432), [point((192.5519409, -76.1990432))], [point((192.5519409, 76.1990432))], False, "CARTESIAN"), True, "CONTINUOUS"), segment(trimmed(circle_curve(frame_2d((192.5519409, 0.0)), 76.1990432), [point((192.5519409, 76.1990432))], [point((192.5519409, -76.1990432))], False, "CARTESIAN"), True, "CONTINUOUS")], self_intersect=False)), frame((0.0, 0.0, 0.0), z_axis=(0.0, 1.0, 0.0), x_axis=(0.0, 0.0, 1.0)), (0.0, 0.0, 1.0), 1.0),
        extrude(outline(composite_curve([segment(trimmed(circle_curve(frame_2d((173.4999807, -15.0000005)), 8.0), [point((165.4999807, -15.0000005))], [point((181.4999807, -15.0000005))], False, "CARTESIAN"), True, "CONTINUOUS"), segment(trimmed(circle_curve(frame_2d((173.4999807, -15.0000005)), 8.0), [point((181.4999807, -15.0000005))], [point((165.4999807, -15.0000005))], False, "CARTESIAN"), True, "CONTINUOUS")], self_intersect=False)), frame((0.0, 0.0, 420.0), z_axis=(0.0, 0.0, 1.0), x_axis=(1.0, 0.0, 0.0)), (0.0, 0.0, 1.0), 30.0),
        extrude(outline(polyline([(167.5981725, -19.0000005), (167.5981725, -10.9634957), (173.3744104, -10.9634957), (173.3744104, -11.9680588), (168.6027356, -11.9680588), (168.6027356, -14.3538961), (173.1232696, -14.3538961), (173.1232696, -15.3584592), (168.6027356, -15.3584592), (168.6027356, -17.9954374), (173.4999807, -17.9954374), (173.4999807, -19.0000005), (167.5981725, -19.0000005)])), frame((0.0, 0.0, 450.0), z_axis=(0.0, 0.0, 1.0), x_axis=(1.0, 0.0, 0.0)), (0.0, 0.0, 1.0), 1.0),
        extrude(outline(polyline([(175.0068254, -19.0000005), (175.0068254, -10.9634957), (176.0113885, -10.9634957), (176.0113885, -17.9954374), (180.0296409, -17.9954374), (180.0296409, -19.0000005), (175.0068254, -19.0000005)])), frame((0.0, 0.0, 450.0), z_axis=(0.0, 0.0, 1.0), x_axis=(1.0, 0.0, 0.0)), (0.0, 0.0, 1.0), 1.0),
    ])


if __name__ == "__main__":
    model = new_model("IFC4")
    model_context = context("Model", 3, world=origin())
    ifc_project = project(units=[si_unit("LENGTHUNIT", "METRE", prefix="MILLI")], contexts=[model_context])
    site = spatial("IfcSite", under=ifc_project)
    building = spatial("IfcBuilding", under=site)
    placement = place(None, origin())
    specialty_equipment_shape = specialty_equipment_e31fde03(model_context)
    element("IfcBuildingElementProxy", 1, Name="Specialty Equipment", at=placement, inside=building, context=model_context, shape_type="MappedRepresentation", body=[
        mapped(specialty_equipment_shape, transform((0.0, 0.0, 0.0), x_axis=(1.0, 0.0, 0.0), y_axis=(0.0, 1.0, 0.0), z_axis=(0.0, 0.0, 1.0))),
    ])
    save(model, "model.ifc")
